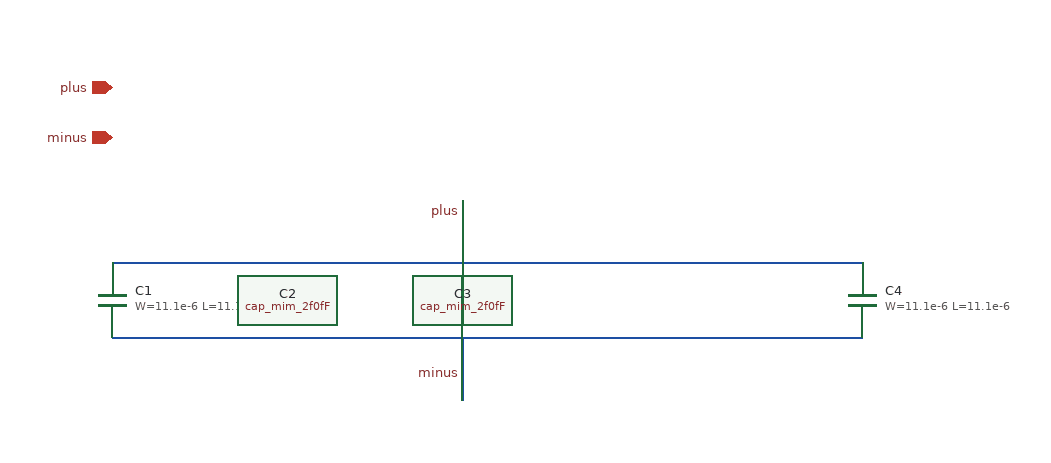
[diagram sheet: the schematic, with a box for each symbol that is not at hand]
v {xschem version=3.4.8RC file_version=1.3}
G {}
K {}
V {}
S {}
F {}
E {}
N 60 -80 660 -80 {lab=plus}
N 60 -20 660 -20 {lab=minus}
N 340 -130 340 -80 {lab=plus}
N 340 -20 340 30 {lab=minus}
C {lab_pin.sym} 340 -120 0 0 {name=p1 sig_type=std_logic lab=plus}
C {lab_pin.sym} 340 10 0 0 {name=p2 sig_type=std_logic lab=minus}
C {ipin.sym} 60 -220 0 0 {name=p3 lab=plus}
C {ipin.sym} 60 -180 0 0 {name=p4 lab=minus}
C {symbols/cap_mim_2f0fF.sym} 60 -50 0 0 {name=C1
W=11.1e-6
L=11.1e-6
model=cap_mim_2f0fF
spiceprefix=X
m=1}
C {symbols/cap_mim_2f0fF.sym} 200 -50 0 0 {name=C2
W=11.1e-6
L=11.1e-6
model=cap_mim_2f0fF
spiceprefix=X
m=1}
C {symbols/cap_mim_2f0fF.sym} 380 -50 0 0 {name=C3
W=11.1e-6
L=11.1e-6
model=cap_mim_2f0fF
spiceprefix=X
m=1}
C {symbols/cap_mim_2f0fF.sym} 660 -50 0 0 {name=C4
W=11.1e-6
L=11.1e-6
model=cap_mim_2f0fF
spiceprefix=X
m=1}
